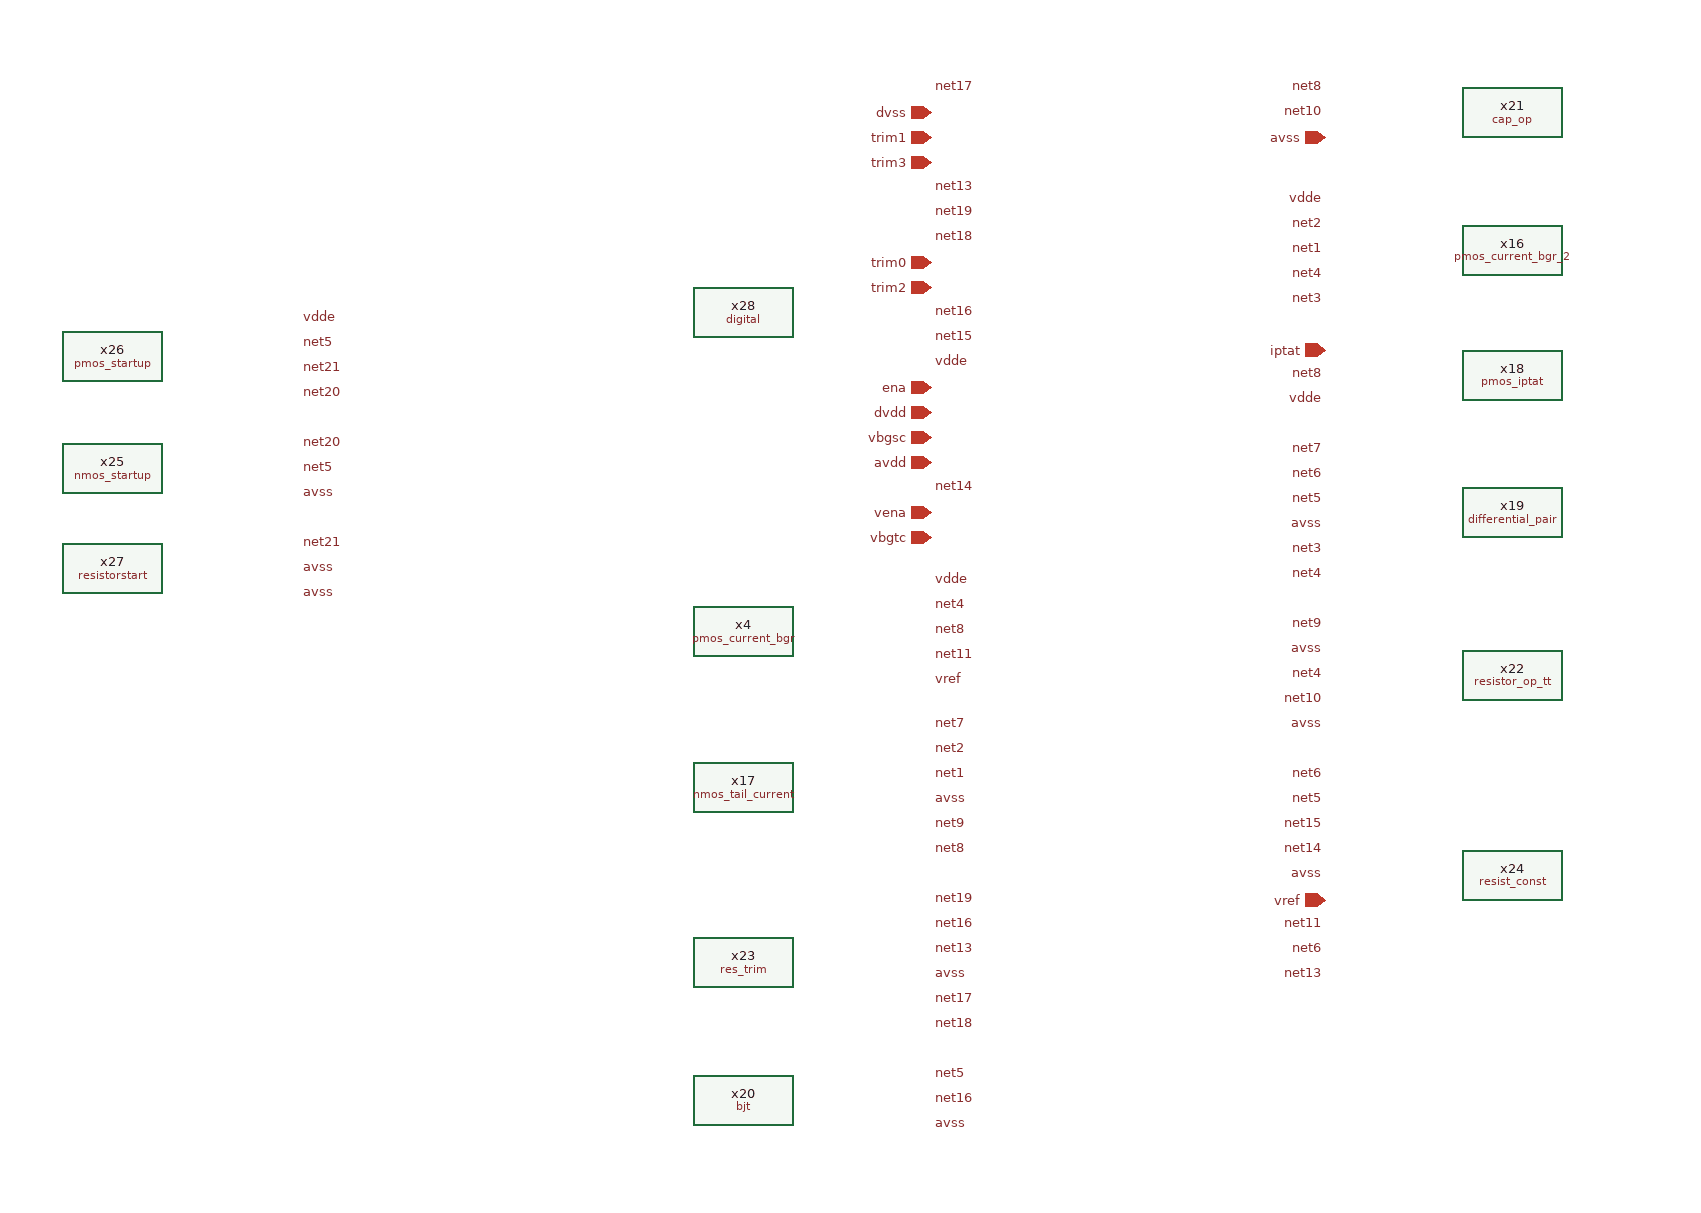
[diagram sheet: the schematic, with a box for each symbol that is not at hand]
v {xschem version=3.4.5 file_version=1.2
}
G {}
K {}
V {}
S {}
E {}
C {pmos_current_bgr.sym} 875 -730 0 0 {name=x4}
C {pmos_current_bgr_2.sym} 1490 -1035 0 1 {name=x16}
C {nmos_tail_current.sym} 875 -605 0 0 {name=x17}
C {pmos_iptat.sym} 1490 -935 2 0 {name=x18}
C {differential_pair.sym} 1490 -825 2 0 {name=x19}
C {bjt.sym} 875 -355 0 0 {name=x20}
C {cap_op.sym} 1490 -1145 2 0 {name=x21}
C {resistor_op_tt.sym} 1490 -695 2 0 {name=x22}
C {res_trim.sym} 875 -465 0 0 {name=x23}
C {resist_const.sym} 1490 -535 2 0 {name=x24}
C {nmos_startup.sym} 370 -860 0 0 {name=x25}
C {pmos_startup.sym} 370 -950 0 0 {name=x26}
C {resistorstart.sym} 370 -780 0 0 {name=x27}
C {digital.sym} 875 -985 0 0 {name=x28}
C {devices/lab_pin.sym} 1340 -1035 0 0 {name=p21 sig_type=std_logic lab=net1}
C {devices/lab_pin.sym} 1025 -615 2 0 {name=p32 sig_type=std_logic lab=net1}
C {devices/lab_pin.sym} 1340 -1055 0 0 {name=p33 sig_type=std_logic lab=net2}
C {devices/lab_pin.sym} 1025 -635 2 0 {name=p34 sig_type=std_logic lab=net2}
C {devices/lab_pin.sym} 1340 -995 0 0 {name=p64 sig_type=std_logic lab=net3}
C {devices/lab_pin.sym} 1340 -795 0 0 {name=p65 sig_type=std_logic lab=net3}
C {devices/lab_pin.sym} 1340 -1015 0 0 {name=p66 sig_type=std_logic lab=net4}
C {devices/lab_pin.sym} 1340 -775 0 0 {name=p67 sig_type=std_logic lab=net4}
C {devices/lab_pin.sym} 1340 -1075 0 0 {name=p68 sig_type=std_logic lab=vdde}
C {devices/lab_pin.sym} 1025 -945 2 0 {name=p69 sig_type=std_logic lab=vdde}
C {devices/lab_pin.sym} 1025 -770 2 0 {name=p70 sig_type=std_logic lab=vdde}
C {devices/lab_pin.sym} 1340 -915 0 0 {name=p71 sig_type=std_logic lab=vdde}
C {devices/lab_pin.sym} 520 -980 2 0 {name=p72 sig_type=std_logic lab=vdde}
C {devices/lab_pin.sym} 520 -760 2 0 {name=p73 sig_type=std_logic lab=avss}
C {devices/lab_pin.sym} 520 -840 2 0 {name=p74 sig_type=std_logic lab=avss}
C {devices/lab_pin.sym} 1025 -455 2 0 {name=p78 sig_type=std_logic lab=avss}
C {devices/lab_pin.sym} 1025 -335 2 0 {name=p79 sig_type=std_logic lab=avss}
C {devices/lab_pin.sym} 1340 -535 0 0 {name=p80 sig_type=std_logic lab=avss}
C {devices/lab_pin.sym} 1340 -835 0 0 {name=p81 sig_type=std_logic lab=net5}
C {devices/lab_pin.sym} 1340 -815 0 0 {name=p82 sig_type=std_logic lab=avss}
C {devices/lab_pin.sym} 1025 -375 2 0 {name=p83 sig_type=std_logic lab=net5}
C {devices/lab_pin.sym} 1340 -855 0 0 {name=p84 sig_type=std_logic lab=net6}
C {devices/lab_pin.sym} 1340 -875 0 0 {name=p85 sig_type=std_logic lab=net7}
C {devices/lab_pin.sym} 1025 -655 2 0 {name=p86 sig_type=std_logic lab=net7}
C {devices/lab_pin.sym} 1025 -595 2 0 {name=p87 sig_type=std_logic lab=avss}
C {devices/lab_pin.sym} 1025 -555 2 0 {name=p88 sig_type=std_logic lab=net8}
C {devices/lab_pin.sym} 1025 -730 2 0 {name=p89 sig_type=std_logic lab=net8}
C {devices/lab_pin.sym} 1025 -575 2 0 {name=p90 sig_type=std_logic lab=net9}
C {devices/lab_pin.sym} 1340 -735 0 0 {name=p109 sig_type=std_logic lab=net9}
C {devices/lab_pin.sym} 1340 -655 0 0 {name=p110 sig_type=std_logic lab=avss}
C {devices/lab_pin.sym} 1340 -715 0 0 {name=p111 sig_type=std_logic lab=avss}
C {devices/lab_pin.sym} 1025 -750 2 0 {name=p112 sig_type=std_logic lab=net4}
C {devices/lab_pin.sym} 1340 -695 0 0 {name=p113 sig_type=std_logic lab=net4}
C {devices/lab_pin.sym} 1340 -1165 0 0 {name=p114 sig_type=std_logic lab=net8}
C {devices/lab_pin.sym} 1340 -675 0 0 {name=p115 sig_type=std_logic lab=net10}
C {devices/lab_pin.sym} 1340 -1145 0 0 {name=p116 sig_type=std_logic lab=net10}
C {devices/lab_pin.sym} 1340 -935 0 0 {name=p117 sig_type=std_logic lab=net8}
C {devices/lab_pin.sym} 1025 -710 2 0 {name=p118 sig_type=std_logic lab=net11}
C {devices/lab_pin.sym} 1340 -495 0 0 {name=p119 sig_type=std_logic lab=net11}
C {devices/lab_pin.sym} 1025 -690 2 0 {name=p120 sig_type=std_logic lab=vref}
C {devices/lab_pin.sym} 1340 -595 0 0 {name=p121 sig_type=std_logic lab=net5}
C {devices/lab_pin.sym} 1340 -615 0 0 {name=p122 sig_type=std_logic lab=net6}
C {devices/lab_pin.sym} 1340 -475 0 0 {name=p123 sig_type=std_logic lab=net6}
C {devices/lab_pin.sym} 1340 -455 0 0 {name=p124 sig_type=std_logic lab=net13}
C {devices/lab_pin.sym} 1025 -475 2 0 {name=p125 sig_type=std_logic lab=net13}
C {devices/lab_pin.sym} 1025 -845 2 0 {name=p126 sig_type=std_logic lab=net14}
C {devices/lab_pin.sym} 1340 -555 0 0 {name=p127 sig_type=std_logic lab=net14}
C {devices/lab_pin.sym} 1340 -575 0 0 {name=p128 sig_type=std_logic lab=net15}
C {devices/lab_pin.sym} 1025 -965 2 0 {name=p129 sig_type=std_logic lab=net15}
C {devices/lab_pin.sym} 1025 -495 2 0 {name=p130 sig_type=std_logic lab=net16}
C {devices/lab_pin.sym} 1025 -355 2 0 {name=p131 sig_type=std_logic lab=net16}
C {devices/lab_pin.sym} 1025 -1085 2 0 {name=p132 sig_type=std_logic lab=net13}
C {devices/lab_pin.sym} 1025 -985 2 0 {name=p133 sig_type=std_logic lab=net16}
C {devices/lab_pin.sym} 1025 -435 2 0 {name=p134 sig_type=std_logic lab=net17}
C {devices/lab_pin.sym} 1025 -1165 2 0 {name=p135 sig_type=std_logic lab=net17}
C {devices/lab_pin.sym} 1025 -1045 2 0 {name=p136 sig_type=std_logic lab=net18}
C {devices/lab_pin.sym} 1025 -415 2 0 {name=p137 sig_type=std_logic lab=net18}
C {devices/lab_pin.sym} 1025 -515 2 0 {name=p138 sig_type=std_logic lab=net19}
C {devices/lab_pin.sym} 1025 -1065 2 0 {name=p139 sig_type=std_logic lab=net19}
C {devices/lab_pin.sym} 520 -920 2 0 {name=p140 sig_type=std_logic lab=net20}
C {devices/lab_pin.sym} 520 -880 2 0 {name=p141 sig_type=std_logic lab=net20}
C {devices/lab_pin.sym} 520 -940 2 0 {name=p142 sig_type=std_logic lab=net21}
C {devices/lab_pin.sym} 520 -800 2 0 {name=p143 sig_type=std_logic lab=net21}
C {devices/lab_pin.sym} 520 -780 2 0 {name=p144 sig_type=std_logic lab=avss}
C {devices/lab_pin.sym} 520 -960 2 0 {name=p145 sig_type=std_logic lab=net5}
C {devices/lab_pin.sym} 520 -860 2 0 {name=p146 sig_type=std_logic lab=net5}
C {devices/iopin.sym} 1025 -1125 0 0 {name=p147 lab=trim1}
C {devices/iopin.sym} 1025 -1105 0 0 {name=p148 lab=trim3}
C {devices/iopin.sym} 1025 -1025 0 0 {name=p149 lab=trim0}
C {devices/iopin.sym} 1025 -1005 0 0 {name=p150 lab=trim2}
C {devices/iopin.sym} 1025 -905 0 0 {name=p151 lab=dvdd}
C {devices/iopin.sym} 1025 -885 0 0 {name=p152 lab=vbgsc}
C {devices/iopin.sym} 1025 -805 0 0 {name=p153 lab=vbgtc}
C {devices/iopin.sym} 1025 -865 0 0 {name=p154 lab=avdd}
C {devices/iopin.sym} 1025 -825 0 0 {name=p155 lab=vena}
C {devices/iopin.sym} 1025 -925 0 0 {name=p156 lab=ena}
C {devices/iopin.sym} 1340 -1125 2 0 {name=p157 lab=avss}
C {devices/iopin.sym} 1025 -1145 0 0 {name=p158 lab=dvss}
C {devices/iopin.sym} 1340 -955 2 0 {name=p159 lab=iptat}
C {devices/iopin.sym} 1340 -515 2 0 {name=p160 lab=vref}
